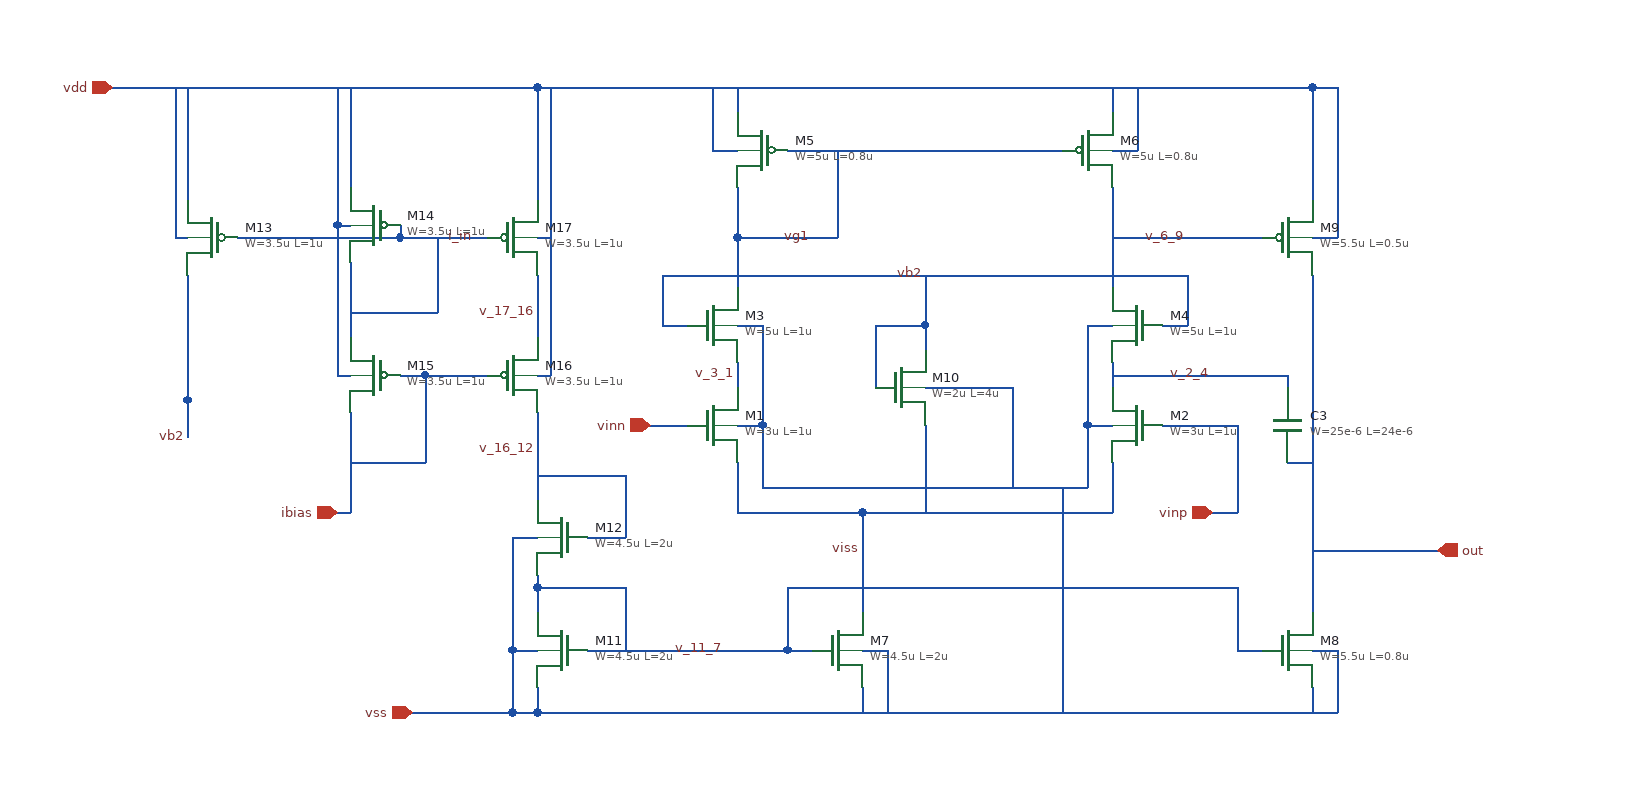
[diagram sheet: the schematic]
v {xschem version=3.4.7 file_version=1.2}
G {}
K {}
V {}
S {}
E {}
N 600 -420 600 -380 {lab=viss}
N 900 -420 900 -380 {lab=viss}
N 1060 -270 1080 -270 {lab=vss}
N 1080 -270 1080 -220 {lab=vss}
N 440 -220 1080 -220 {lab=vss}
N 1060 -240 1060 -220 {lab=vss}
N 1060 -350 1160 -350 {lab=out}
N 440 -720 1060 -720 {lab=vdd}
N 1060 -720 1080 -720 {lab=vdd}
N 900 -670 920 -670 {lab=vdd}
N 920 -720 920 -670 {lab=vdd}
N 900 -720 900 -700 {lab=vdd}
N 740 -670 860 -670 {lab=vg1}
N 600 -720 600 -700 {lab=vdd}
N 600 -640 600 -600 {lab=vg1}
N 600 -600 680 -600 {lab=vg1}
N 680 -670 680 -600 {lab=vg1}
N 580 -670 600 -670 {lab=vdd}
N 580 -720 580 -670 {lab=vdd}
N 600 -450 620 -450 {lab=vss}
N 620 -450 620 -400 {lab=vss}
N 720 -400 880 -400 {lab=vss}
N 880 -450 880 -400 {lab=vss}
N 880 -450 900 -450 {lab=vss}
N 620 -530 620 -450 {lab=vss}
N 880 -530 900 -530 {lab=vss}
N 880 -530 880 -450 {lab=vss}
N 600 -500 600 -480 {lab=v_3_1}
N 900 -500 900 -480 {lab=v_2_4}
N 900 -640 900 -560 {lab=v_6_9}
N 600 -600 600 -560 {lab=vg1}
N 700 -380 700 -300 {lab=viss}
N 700 -240 700 -220 {lab=vss}
N 700 -380 700 -300 {lab=viss}
N 700 -240 700 -220 {lab=vss}
N 700 -270 720 -270 {lab=vss}
N 720 -270 720 -220 {lab=vss}
N 1000 -270 1020 -270 {lab=v_11_7}
N 1000 -320 1000 -270 {lab=v_11_7}
N 740 -320 1000 -320 {lab=v_11_7}
N 640 -320 640 -270 {lab=v_11_7}
N 640 -270 660 -270 {lab=v_11_7}
N 480 -270 640 -270 {lab=v_11_7}
N 420 -270 440 -270 {lab=vss}
N 440 -240 440 -220 {lab=vss}
N 420 -270 420 -220 {lab=vss}
N 440 -320 440 -300 {lab=v_11_7}
N 1060 -600 1080 -600 {lab=vdd}
N 1080 -720 1080 -600 {lab=vdd}
N 1060 -570 1060 -510 {lab=out}
N 1060 -720 1060 -630 {lab=vdd}
N 940 -530 960 -530 {lab=vb2}
N 940 -450 960 -450 {lab=vinp}
N 960 -450 1000 -450 {lab=vinp}
N 540 -530 560 -530 {lab=vb2}
N 1000 -450 1000 -380 {lab=vinp}
N 980 -380 1000 -380 {lab=vinp}
N 700 -380 900 -380 {lab=viss}
N 860 -400 860 -220 {lab=vss}
N 540 -540 540 -530 {lab=vb2}
N 540 -570 540 -540 {lab=vb2}
N 960 -570 960 -530 {lab=vb2}
N 620 -400 720 -400 {lab=vss}
N 600 -380 700 -380 {lab=viss}
N 640 -320 740 -320 {lab=v_11_7}
N 540 -570 640 -570 {lab=vb2}
N 640 -670 740 -670 {lab=vg1}
N 420 -220 440 -220 {lab=vss}
N 340 -720 440 -720 {lab=vdd}
N 340 -220 420 -220 {lab=vss}
N 240 -720 340 -720 {lab=vdd}
N 290 -720 290 -640 {lab=vdd}
N 440 -720 440 -640 {lab=vdd}
N 450 -720 450 -610 {lab=vdd}
N 330 -600 400 -600 {lab=i_in}
N 160 -720 160 -640 {lab=vdd}
N 150 -720 160 -720 {lab=vdd}
N 150 -720 150 -670 {lab=vdd}
N 100 -720 240 -720 {lab=vdd}
N 280 -380 290 -380 {lab=ibias}
N 640 -570 960 -570 {lab=vb2}
N 160 -470 160 -440 {lab=vb2}
N 160 -480 160 -470 {lab=vb2}
N 150 -670 150 -610 {lab=vdd}
N 440 -560 440 -530 {lab=v_17_16}
N 450 -610 450 -500 {lab=vdd}
N 290 -560 290 -530 {lab=i_in}
N 280 -610 280 -500 {lab=vdd}
N 280 -720 280 -610 {lab=vdd}
N 290 -450 290 -380 {lab=ibias}
N 290 -420 350 -420 {lab=ibias}
N 350 -490 350 -420 {lab=ibias}
N 290 -540 360 -540 {lab=i_in}
N 360 -600 360 -540 {lab=i_in}
N 200 -600 330 -600 {lab=i_in}
N 710 -530 710 -480 {lab=vb2}
N 710 -530 750 -530 {lab=vb2}
N 970 -490 980 -490 {lab=v_2_4}
N 900 -490 910 -490 {lab=v_2_4}
N 530 -450 560 -450 {lab=vinn}
N 440 -330 440 -320 {lab=v_11_7}
N 510 -320 510 -270 {lab=v_11_7}
N 380 -490 400 -490 {lab=ibias}
N 330 -490 350 -490 {lab=ibias}
N 350 -490 380 -490 {lab=ibias}
N 600 -530 620 -530 {lab=vss}
N 750 -450 750 -380 {lab=viss}
N 750 -480 820 -480 {lab=vss}
N 820 -480 820 -400 {lab=vss}
N 750 -570 750 -530 {lab=vb2}
N 750 -530 750 -510 {lab=vb2}
N 1000 -600 1020 -600 {lab=v_6_9}
N 980 -490 990 -490 {lab=v_2_4}
N 160 -560 160 -470 {lab=vb2}
N 480 -360 510 -360 {lab=v_16_12}
N 510 -410 510 -360 {lab=v_16_12}
N 440 -410 510 -410 {lab=v_16_12}
N 440 -450 440 -390 {lab=v_16_12}
N 440 -320 510 -320 {lab=v_11_7}
N 420 -360 440 -360 {lab=vss}
N 420 -360 420 -270 {lab=vss}
N 900 -600 1000 -600 {lab=v_6_9}
N 910 -490 970 -490 {lab=v_2_4}
N 1060 -510 1060 -300 {lab=out}
N 1040 -420 1060 -420 {lab=out}
N 1040 -490 1040 -480 {lab=v_2_4}
N 990 -490 1040 -490 {lab=v_2_4}
N 160 -640 160 -630 {lab=vdd}
N 150 -610 150 -600 {lab=vdd}
N 150 -600 160 -600 {lab=vdd}
N 160 -570 160 -560 {lab=vb2}
N 330 -610 330 -600 {lab=i_in}
N 280 -610 290 -610 {lab=vdd}
N 290 -580 290 -560 {lab=i_in}
N 290 -530 290 -520 {lab=i_in}
N 290 -460 290 -450 {lab=ibias}
N 280 -500 280 -490 {lab=vdd}
N 280 -490 290 -490 {lab=vdd}
N 440 -530 440 -520 {lab=v_17_16}
N 450 -500 450 -490 {lab=vdd}
N 440 -490 450 -490 {lab=vdd}
N 440 -460 440 -450 {lab=v_16_12}
N 440 -570 440 -560 {lab=v_17_16}
N 440 -640 440 -630 {lab=vdd}
N 440 -600 450 -600 {lab=vdd}
C {title.sym} 160 -40 0 0 {name=l1 author="X.J. Lee"}
C {symbols/nfet_03v3.sym} 580 -450 0 0 {name=M1
L=1u
W=3u
nf=1
m=1
ad="'int((nf+1)/2) * W/nf * 0.18u'"
pd="'2*int((nf+1)/2) * (W/nf + 0.18u)'"
as="'int((nf+2)/2) * W/nf * 0.18u'"
ps="'2*int((nf+2)/2) * (W/nf + 0.18u)'"
nrd="'0.18u / W'" nrs="'0.18u / W'"
sa=0 sb=0 sd=0
model=nfet_03v3
spiceprefix=X
}
C {opin.sym} 1160 -350 0 0 {name=p1 lab=out}
C {ipin.sym} 100 -720 0 0 {name=p2 lab=vdd}
C {ipin.sym} 340 -220 0 0 {name=p3 lab=vss}
C {ipin.sym} 530 -450 0 0 {name=p4 lab=vinn}
C {symbols/nfet_03v3.sym} 920 -450 0 1 {name=M2
L=1u
W=3u
nf=1
m=1
ad="'int((nf+1)/2) * W/nf * 0.18u'"
pd="'2*int((nf+1)/2) * (W/nf + 0.18u)'"
as="'int((nf+2)/2) * W/nf * 0.18u'"
ps="'2*int((nf+2)/2) * (W/nf + 0.18u)'"
nrd="'0.18u / W'" nrs="'0.18u / W'"
sa=0 sb=0 sd=0
model=nfet_03v3
spiceprefix=X
}
C {symbols/pfet_03v3.sym} 880 -670 0 0 {name=M6
L=0.8u
W=5u
nf=1
m=5
ad="'int((nf+1)/2) * W/nf * 0.18u'"
pd="'2*int((nf+1)/2) * (W/nf + 0.18u)'"
as="'int((nf+2)/2) * W/nf * 0.18u'"
ps="'2*int((nf+2)/2) * (W/nf + 0.18u)'"
nrd="'0.18u / W'" nrs="'0.18u / W'"
sa=0 sb=0 sd=0
model=pfet_03v3
spiceprefix=X
}
C {symbols/pfet_03v3.sym} 620 -670 0 1 {name=M5
L=0.8u
W=5u
nf=1
m=5
ad="'int((nf+1)/2) * W/nf * 0.18u'"
pd="'2*int((nf+1)/2) * (W/nf + 0.18u)'"
as="'int((nf+2)/2) * W/nf * 0.18u'"
ps="'2*int((nf+2)/2) * (W/nf + 0.18u)'"
nrd="'0.18u / W'" nrs="'0.18u / W'"
sa=0 sb=0 sd=0
model=pfet_03v3
spiceprefix=X
}
C {ipin.sym} 280 -380 0 0 {name=p5 lab=ibias}
C {ipin.sym} 980 -380 0 0 {name=p6 lab=vinp}
C {symbols/nfet_03v3.sym} 920 -530 0 1 {name=M4
L=1u
W=5u
nf=1
m=6
ad="'int((nf+1)/2) * W/nf * 0.18u'"
pd="'2*int((nf+1)/2) * (W/nf + 0.18u)'"
as="'int((nf+2)/2) * W/nf * 0.18u'"
ps="'2*int((nf+2)/2) * (W/nf + 0.18u)'"
nrd="'0.18u / W'" nrs="'0.18u / W'"
sa=0 sb=0 sd=0
model=nfet_03v3
spiceprefix=X
}
C {symbols/nfet_03v3.sym} 580 -530 0 0 {name=M3
L=1u
W=5u
nf=1
m=6
ad="'int((nf+1)/2) * W/nf * 0.18u'"
pd="'2*int((nf+1)/2) * (W/nf + 0.18u)'"
as="'int((nf+2)/2) * W/nf * 0.18u'"
ps="'2*int((nf+2)/2) * (W/nf + 0.18u)'"
nrd="'0.18u / W'" nrs="'0.18u / W'"
sa=0 sb=0 sd=0
model=nfet_03v3
spiceprefix=X
}
C {symbols/nfet_03v3.sym} 680 -270 0 0 {name=M7
L=2u
W=4.5u
nf=1
m=3
ad="'int((nf+1)/2) * W/nf * 0.18u'"
pd="'2*int((nf+1)/2) * (W/nf + 0.18u)'"
as="'int((nf+2)/2) * W/nf * 0.18u'"
ps="'2*int((nf+2)/2) * (W/nf + 0.18u)'"
nrd="'0.18u / W'" nrs="'0.18u / W'"
sa=0 sb=0 sd=0
model=nfet_03v3
spiceprefix=X
}
C {symbols/nfet_03v3.sym} 460 -270 0 1 {name=M11
L=2u
W=4.5u
nf=1
m=1
ad="'int((nf+1)/2) * W/nf * 0.18u'"
pd="'2*int((nf+1)/2) * (W/nf + 0.18u)'"
as="'int((nf+2)/2) * W/nf * 0.18u'"
ps="'2*int((nf+2)/2) * (W/nf + 0.18u)'"
nrd="'0.18u / W'" nrs="'0.18u / W'"
sa=0 sb=0 sd=0
model=nfet_03v3
spiceprefix=X
}
C {lab_wire.sym} 660 -600 0 0 {name=p7 sig_type=std_logic lab=vg1}
C {lab_wire.sym} 700 -350 0 0 {name=p9 sig_type=std_logic lab=viss}
C {lab_wire.sym} 750 -570 0 0 {name=p11 sig_type=std_logic lab=vb2}
C {symbols/nfet_03v3.sym} 730 -480 0 0 {name=M10
L=4u
W=2u
nf=1
m=1
ad="'int((nf+1)/2) * W/nf * 0.18u'"
pd="'2*int((nf+1)/2) * (W/nf + 0.18u)'"
as="'int((nf+2)/2) * W/nf * 0.18u'"
ps="'2*int((nf+2)/2) * (W/nf + 0.18u)'"
nrd="'0.18u / W'" nrs="'0.18u / W'"
sa=0 sb=0 sd=0
model=nfet_03v3
spiceprefix=X
}
C {lab_wire.sym} 160 -440 0 0 {name=p8 sig_type=std_logic lab=vb2}
C {symbols/nfet_03v3.sym} 1040 -270 0 0 {name=M8
L=0.8u
W=5.5u
nf=1
m=2
ad="'int((nf+1)/2) * W/nf * 0.18u'"
pd="'2*int((nf+1)/2) * (W/nf + 0.18u)'"
as="'int((nf+2)/2) * W/nf * 0.18u'"
ps="'2*int((nf+2)/2) * (W/nf + 0.18u)'"
nrd="'0.18u / W'" nrs="'0.18u / W'"
sa=0 sb=0 sd=0
model=nfet_03v3
spiceprefix=X
}
C {symbols/pfet_03v3.sym} 1040 -600 0 0 {name=M9
L=0.5u
W=5.5u
nf= 1
m=14
ad="'int((nf+1)/2) * W/nf * 0.18u'"
pd="'2*int((nf+1)/2) * (W/nf + 0.18u)'"
as="'int((nf+2)/2) * W/nf * 0.18u'"
ps="'2*int((nf+2)/2) * (W/nf + 0.18u)'"
nrd="'0.18u / W'" nrs="'0.18u / W'"
sa=0 sb=0 sd=0
model=pfet_03v3
spiceprefix=X
}
C {symbols/nfet_03v3.sym} 460 -360 0 1 {name=M12
L=2u
W=4.5u
nf=1
m=1
ad="'int((nf+1)/2) * W/nf * 0.18u'"
pd="'2*int((nf+1)/2) * (W/nf + 0.18u)'"
as="'int((nf+2)/2) * W/nf * 0.18u'"
ps="'2*int((nf+2)/2) * (W/nf + 0.18u)'"
nrd="'0.18u / W'" nrs="'0.18u / W'"
sa=0 sb=0 sd=0
model=nfet_03v3
spiceprefix=X
}
C {symbols/pfet_03v3.sym} 180 -600 0 1 {name=M13
L=1u
W=3.5u
nf=1
m=1
ad="'int((nf+1)/2) * W/nf * 0.18u'"
pd="'2*int((nf+1)/2) * (W/nf + 0.18u)'"
as="'int((nf+2)/2) * W/nf * 0.18u'"
ps="'2*int((nf+2)/2) * (W/nf + 0.18u)'"
nrd="'0.18u / W'" nrs="'0.18u / W'"
sa=0 sb=0 sd=0
model=pfet_03v3
spiceprefix=X
}
C {symbols/pfet_03v3.sym} 310 -610 0 1 {name=M14
L=1u
W=3.5u
nf=1
m=1
ad="'int((nf+1)/2) * W/nf * 0.18u'"
pd="'2*int((nf+1)/2) * (W/nf + 0.18u)'"
as="'int((nf+2)/2) * W/nf * 0.18u'"
ps="'2*int((nf+2)/2) * (W/nf + 0.18u)'"
nrd="'0.18u / W'" nrs="'0.18u / W'"
sa=0 sb=0 sd=0
model=pfet_03v3
spiceprefix=X
}
C {symbols/pfet_03v3.sym} 310 -490 0 1 {name=M15
L=1u
W=3.5u
nf=1
m=1
ad="'int((nf+1)/2) * W/nf * 0.18u'"
pd="'2*int((nf+1)/2) * (W/nf + 0.18u)'"
as="'int((nf+2)/2) * W/nf * 0.18u'"
ps="'2*int((nf+2)/2) * (W/nf + 0.18u)'"
nrd="'0.18u / W'" nrs="'0.18u / W'"
sa=0 sb=0 sd=0
model=pfet_03v3
spiceprefix=X
}
C {symbols/pfet_03v3.sym} 420 -490 0 0 {name=M16
L=1u
W=3.5u
nf=1
m=1
ad="'int((nf+1)/2) * W/nf * 0.18u'"
pd="'2*int((nf+1)/2) * (W/nf + 0.18u)'"
as="'int((nf+2)/2) * W/nf * 0.18u'"
ps="'2*int((nf+2)/2) * (W/nf + 0.18u)'"
nrd="'0.18u / W'" nrs="'0.18u / W'"
sa=0 sb=0 sd=0
model=pfet_03v3
spiceprefix=X
}
C {symbols/pfet_03v3.sym} 420 -600 0 0 {name=M17
L=1u
W=3.5u
nf=1
m=1
ad="'int((nf+1)/2) * W/nf * 0.18u'"
pd="'2*int((nf+1)/2) * (W/nf + 0.18u)'"
as="'int((nf+2)/2) * W/nf * 0.18u'"
ps="'2*int((nf+2)/2) * (W/nf + 0.18u)'"
nrd="'0.18u / W'" nrs="'0.18u / W'"
sa=0 sb=0 sd=0
model=pfet_03v3
spiceprefix=X
}
C {symbols/cap_mim_2f0fF.sym} 1040 -450 0 0 {name=C3
W=25e-6
L=24e-6
model=cap_mim_2f0fF
spiceprefix=X
m=1}
C {lab_wire.sym} 980 -490 0 0 {name=p10 sig_type=std_logic lab=v_2_4}
C {lab_wire.sym} 390 -600 0 0 {name=p12 sig_type=std_logic lab=i_in}
C {lab_wire.sym} 440 -430 0 0 {name=p13 sig_type=std_logic lab=v_16_12}
C {lab_wire.sym} 590 -270 0 0 {name=p14 sig_type=std_logic lab=v_11_7}
C {lab_wire.sym} 960 -600 0 0 {name=p16 sig_type=std_logic lab=v_6_9}
C {lab_wire.sym} 440 -540 0 0 {name=p15 sig_type=std_logic lab=v_17_16}
C {lab_wire.sym} 600 -490 0 0 {name=p17 sig_type=std_logic lab=v_3_1}
